One B-rep face of a CAD part: STEP entity #23986.
In plain terms, the planar face has unit normal (0, 0, 1).
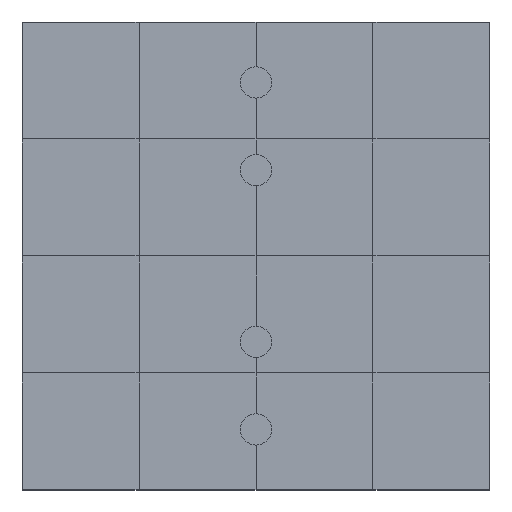
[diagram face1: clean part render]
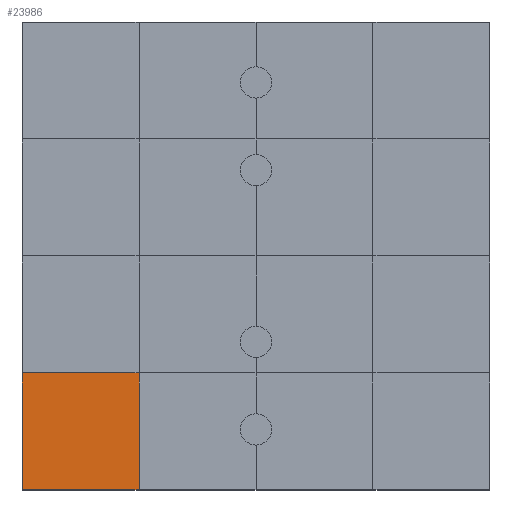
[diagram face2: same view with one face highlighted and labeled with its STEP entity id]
Its self-contained STEP definition (entity closure, numbers rounded to 3 decimals):
#23797 = VERTEX_POINT('',#23798);
#23798 = CARTESIAN_POINT('',(0.,0.,1.5));
#23805 = PLANE('',#23806);
#23806 = AXIS2_PLACEMENT_3D('',#23807,#23808,#23809);
#23807 = CARTESIAN_POINT('',(0.,0.,0.));
#23808 = DIRECTION('',(1.,0.,-0.));
#23809 = DIRECTION('',(0.,0.,1.));
#23817 = PLANE('',#23818);
#23818 = AXIS2_PLACEMENT_3D('',#23819,#23820,#23821);
#23819 = CARTESIAN_POINT('',(0.,0.,0.));
#23820 = DIRECTION('',(-0.,1.,0.));
#23821 = DIRECTION('',(0.,0.,1.));
#23858 = VERTEX_POINT('',#23859);
#23859 = CARTESIAN_POINT('',(0.,3.,1.5));
#23885 = EDGE_CURVE('',#23797,#23858,#23886,.T.);
#23886 = SURFACE_CURVE('',#23887,(#23891,#23898),.PCURVE_S1.);
#23887 = LINE('',#23888,#23889);
#23888 = CARTESIAN_POINT('',(0.,0.,1.5));
#23889 = VECTOR('',#23890,1.);
#23890 = DIRECTION('',(-0.,1.,0.));
#23891 = PCURVE('',#23805,#23892);
#23892 = DEFINITIONAL_REPRESENTATION('',(#23893),#23897);
#23893 = LINE('',#23894,#23895);
#23894 = CARTESIAN_POINT('',(1.5,0.));
#23895 = VECTOR('',#23896,1.);
#23896 = DIRECTION('',(0.,-1.));
#23897 = ( GEOMETRIC_REPRESENTATION_CONTEXT(2) 
PARAMETRIC_REPRESENTATION_CONTEXT() REPRESENTATION_CONTEXT('2D SPACE',''
  ) );
#23898 = PCURVE('',#23899,#23904);
#23899 = PLANE('',#23900);
#23900 = AXIS2_PLACEMENT_3D('',#23901,#23902,#23903);
#23901 = CARTESIAN_POINT('',(0.,0.,1.5));
#23902 = DIRECTION('',(0.,0.,1.));
#23903 = DIRECTION('',(1.,0.,-0.));
#23904 = DEFINITIONAL_REPRESENTATION('',(#23905),#23909);
#23905 = LINE('',#23906,#23907);
#23906 = CARTESIAN_POINT('',(0.,0.));
#23907 = VECTOR('',#23908,1.);
#23908 = DIRECTION('',(0.,1.));
#23909 = ( GEOMETRIC_REPRESENTATION_CONTEXT(2) 
PARAMETRIC_REPRESENTATION_CONTEXT() REPRESENTATION_CONTEXT('2D SPACE',''
  ) );
#23938 = EDGE_CURVE('',#23797,#23939,#23941,.T.);
#23939 = VERTEX_POINT('',#23940);
#23940 = CARTESIAN_POINT('',(3.,0.,1.5));
#23941 = SURFACE_CURVE('',#23942,(#23946,#23953),.PCURVE_S1.);
#23942 = LINE('',#23943,#23944);
#23943 = CARTESIAN_POINT('',(0.,0.,1.5));
#23944 = VECTOR('',#23945,1.);
#23945 = DIRECTION('',(1.,0.,-0.));
#23946 = PCURVE('',#23817,#23947);
#23947 = DEFINITIONAL_REPRESENTATION('',(#23948),#23952);
#23948 = LINE('',#23949,#23950);
#23949 = CARTESIAN_POINT('',(1.5,0.));
#23950 = VECTOR('',#23951,1.);
#23951 = DIRECTION('',(0.,1.));
#23952 = ( GEOMETRIC_REPRESENTATION_CONTEXT(2) 
PARAMETRIC_REPRESENTATION_CONTEXT() REPRESENTATION_CONTEXT('2D SPACE',''
  ) );
#23953 = PCURVE('',#23899,#23954);
#23954 = DEFINITIONAL_REPRESENTATION('',(#23955),#23959);
#23955 = LINE('',#23956,#23957);
#23956 = CARTESIAN_POINT('',(0.,0.));
#23957 = VECTOR('',#23958,1.);
#23958 = DIRECTION('',(1.,0.));
#23959 = ( GEOMETRIC_REPRESENTATION_CONTEXT(2) 
PARAMETRIC_REPRESENTATION_CONTEXT() REPRESENTATION_CONTEXT('2D SPACE',''
  ) );
#23986 = ADVANCED_FACE('',(#23987),#23899,.T.);
#23987 = FACE_BOUND('',#23988,.T.);
#23988 = EDGE_LOOP('',(#23989,#23990,#23991,#24019));
#23989 = ORIENTED_EDGE('',*,*,#23885,.F.);
#23990 = ORIENTED_EDGE('',*,*,#23938,.T.);
#23991 = ORIENTED_EDGE('',*,*,#23992,.T.);
#23992 = EDGE_CURVE('',#23939,#23993,#23995,.T.);
#23993 = VERTEX_POINT('',#23994);
#23994 = CARTESIAN_POINT('',(3.,3.,1.5));
#23995 = SURFACE_CURVE('',#23996,(#24000,#24007),.PCURVE_S1.);
#23996 = LINE('',#23997,#23998);
#23997 = CARTESIAN_POINT('',(3.,0.,1.5));
#23998 = VECTOR('',#23999,1.);
#23999 = DIRECTION('',(-0.,1.,0.));
#24000 = PCURVE('',#23899,#24001);
#24001 = DEFINITIONAL_REPRESENTATION('',(#24002),#24006);
#24002 = LINE('',#24003,#24004);
#24003 = CARTESIAN_POINT('',(3.,0.));
#24004 = VECTOR('',#24005,1.);
#24005 = DIRECTION('',(0.,1.));
#24006 = ( GEOMETRIC_REPRESENTATION_CONTEXT(2) 
PARAMETRIC_REPRESENTATION_CONTEXT() REPRESENTATION_CONTEXT('2D SPACE',''
  ) );
#24007 = PCURVE('',#24008,#24013);
#24008 = PLANE('',#24009);
#24009 = AXIS2_PLACEMENT_3D('',#24010,#24011,#24012);
#24010 = CARTESIAN_POINT('',(3.,0.,1.5));
#24011 = DIRECTION('',(0.,0.,1.));
#24012 = DIRECTION('',(1.,0.,-0.));
#24013 = DEFINITIONAL_REPRESENTATION('',(#24014),#24018);
#24014 = LINE('',#24015,#24016);
#24015 = CARTESIAN_POINT('',(0.,0.));
#24016 = VECTOR('',#24017,1.);
#24017 = DIRECTION('',(0.,1.));
#24018 = ( GEOMETRIC_REPRESENTATION_CONTEXT(2) 
PARAMETRIC_REPRESENTATION_CONTEXT() REPRESENTATION_CONTEXT('2D SPACE',''
  ) );
#24019 = ORIENTED_EDGE('',*,*,#24020,.F.);
#24020 = EDGE_CURVE('',#23858,#23993,#24021,.T.);
#24021 = SURFACE_CURVE('',#24022,(#24026,#24033),.PCURVE_S1.);
#24022 = LINE('',#24023,#24024);
#24023 = CARTESIAN_POINT('',(0.,3.,1.5));
#24024 = VECTOR('',#24025,1.);
#24025 = DIRECTION('',(1.,0.,-0.));
#24026 = PCURVE('',#23899,#24027);
#24027 = DEFINITIONAL_REPRESENTATION('',(#24028),#24032);
#24028 = LINE('',#24029,#24030);
#24029 = CARTESIAN_POINT('',(0.,3.));
#24030 = VECTOR('',#24031,1.);
#24031 = DIRECTION('',(1.,0.));
#24032 = ( GEOMETRIC_REPRESENTATION_CONTEXT(2) 
PARAMETRIC_REPRESENTATION_CONTEXT() REPRESENTATION_CONTEXT('2D SPACE',''
  ) );
#24033 = PCURVE('',#24034,#24039);
#24034 = PLANE('',#24035);
#24035 = AXIS2_PLACEMENT_3D('',#24036,#24037,#24038);
#24036 = CARTESIAN_POINT('',(0.,3.,1.5));
#24037 = DIRECTION('',(0.,0.,1.));
#24038 = DIRECTION('',(1.,0.,-0.));
#24039 = DEFINITIONAL_REPRESENTATION('',(#24040),#24044);
#24040 = LINE('',#24041,#24042);
#24041 = CARTESIAN_POINT('',(0.,0.));
#24042 = VECTOR('',#24043,1.);
#24043 = DIRECTION('',(1.,0.));
#24044 = ( GEOMETRIC_REPRESENTATION_CONTEXT(2) 
PARAMETRIC_REPRESENTATION_CONTEXT() REPRESENTATION_CONTEXT('2D SPACE',''
  ) );
